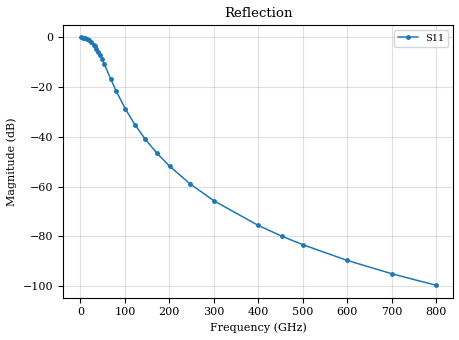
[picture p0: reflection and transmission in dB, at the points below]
! INTERCONNECT S-parameters
# HZ S MA R 50.00
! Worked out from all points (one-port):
!   999 points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, 800 MHz to 799.2 GHz, reference 50 ohm
!   lowest |S11| = -99.6 dB at 799.2 GHz (marker M1), VSWR 1.00, Z = 50 - j0.000184 ohm
!   |S11| at or under -10 dB: 51.71 GHz to end of sweep
!   S11 on the Smith chart (normalised r, x): 800 MHz: 0, +35; 9.6 GHz: 0.15, +2.84; 19.2 GHz: 0.17, +1.23; 29.6 GHz: 0.22, +0.56; 44 GHz: 0.39, +0.05; 799.2 GHz: 1.00, -0.00
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8e8  0.9998 3.2
4.8e9  0.9918 19.4
9.6e9  0.9676 38.8
1.44e10  0.928 58.1
1.92e10  0.874 77.5
2.4e10  0.8069 96.8
2.96e10  0.7142 119.3
3.28e10  0.6559 131.9
3.6e10  0.5951 144.2
4e10  0.5182 159.2
4.4e10  0.4435 173.3
4.88e10  0.361 189.0
5.36e10  0.2897 203.1
6.8e10  0.146 236.1
8.08e10  0.08177 256.4
1.008e11  0.03668 277.6
1.224e11  0.0176 292.6
1.456e11  0.009001 303.6
1.72e11  0.004694 312.4
2.008e11  0.002552 319.3
2.472e11  0.001121 327.0
3.008e11  0.0005144 332.9
4e11  0.0001653 339.6
4.536e11  0.0001001 342.1
5e11  6.787e-05 343.7
6e11  3.277e-05 346.4
7e11  1.77e-05 348.4
7.992e11  1.042e-05 349.8
